VERSION 5.7 ;
  NOWIREEXTENSIONATPIN ON ;
  DIVIDERCHAR "/" ;
  BUSBITCHARS "[]" ;
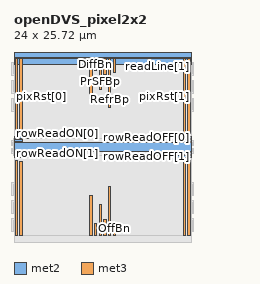
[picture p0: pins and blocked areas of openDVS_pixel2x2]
MACRO openDVS_pixel2x2
  CLASS BLOCK ;
  FOREIGN openDVS_pixel2x2 ;
  ORIGIN 17.915 13.040 ;
  SIZE 24.000 BY 25.720 ;
  PIN rowReadOFF[0]
    ANTENNAGATEAREA 0.420000 ;
    PORT
      LAYER met2 ;
        RECT -17.915 0.930 -15.840 1.190 ;
    END
    PORT
      LAYER met2 ;
        RECT 4.010 0.930 6.085 1.190 ;
    END
  END rowReadOFF[0]
  PIN rowReadON[0]
    ANTENNAGATEAREA 0.420000 ;
    PORT
      LAYER met2 ;
        RECT -17.915 0.530 -16.740 0.790 ;
    END
    PORT
      LAYER met2 ;
        RECT 4.910 0.530 6.085 0.790 ;
    END
  END rowReadON[0]
  PIN GndD
    PORT
      LAYER met2 ;
        RECT -17.915 -0.755 6.085 0.395 ;
    END
  END GndD
  PIN rowReadON[1]
    ANTENNAGATEAREA 0.420000 ;
    PORT
      LAYER met2 ;
        RECT -17.915 -1.150 -16.740 -0.890 ;
    END
    PORT
      LAYER met2 ;
        RECT 4.910 -1.150 6.085 -0.890 ;
    END
  END rowReadON[1]
  PIN rowReadOFF[1]
    ANTENNAGATEAREA 0.420000 ;
    PORT
      LAYER met2 ;
        RECT -17.915 -1.550 -15.840 -1.290 ;
    END
    PORT
      LAYER met2 ;
        RECT 4.010 -1.550 6.085 -1.290 ;
    END
  END rowReadOFF[1]
  PIN GndA
    PORT
      LAYER met2 ;
        RECT -17.915 10.960 6.085 11.750 ;
    END
  END GndA
  PIN VddA18
    PORT
      LAYER met2 ;
        RECT -17.915 11.890 6.085 12.680 ;
    END
  END VddA18
  PIN OffBn
    ANTENNAGATEAREA 9.000000 ;
    PORT
      LAYER met3 ;
        RECT -4.505 -12.180 -4.175 -10.205 ;
    END
    PORT
      LAYER met3 ;
        RECT -4.505 9.845 -4.175 11.820 ;
    END
  END OffBn
  PIN readLine[0]
    ANTENNAGATEAREA 0.126000 ;
    PORT
      LAYER met3 ;
        RECT -17.135 1.735 -16.805 11.820 ;
    END
    PORT
      LAYER met3 ;
        RECT -17.135 -12.180 -16.805 -2.095 ;
    END
  END readLine[0]
  PIN pixRst[1]
    ANTENNADIFFAREA 0.252000 ;
    PORT
      LAYER met3 ;
        RECT 5.605 1.610 5.935 11.820 ;
    END
    PORT
      LAYER met3 ;
        RECT 5.605 -12.180 5.935 -1.970 ;
    END
  END pixRst[1]
  PIN readLine[1]
    ANTENNAGATEAREA 0.126000 ;
    PORT
      LAYER met3 ;
        RECT 4.975 1.735 5.305 11.820 ;
    END
    PORT
      LAYER met3 ;
        RECT 4.975 -12.180 5.305 -2.095 ;
    END
  END readLine[1]
  PIN pixRst[0]
    ANTENNADIFFAREA 0.252000 ;
    PORT
      LAYER met3 ;
        RECT -17.765 1.610 -17.435 11.820 ;
    END
    PORT
      LAYER met3 ;
        RECT -17.765 -12.180 -17.435 -1.970 ;
    END
  END pixRst[0]
  PIN OnBn
    ANTENNAGATEAREA 9.000000 ;
    PORT
      LAYER met3 ;
        RECT -7.655 6.370 -7.325 11.820 ;
    END
    PORT
      LAYER met3 ;
        RECT -7.655 -12.180 -7.325 -6.730 ;
    END
  END OnBn
  PIN DiffBn
    ANTENNAGATEAREA 9.000000 ;
    PORT
      LAYER met3 ;
        RECT -7.025 10.120 -6.695 11.820 ;
    END
    PORT
      LAYER met3 ;
        RECT -7.025 -12.180 -6.695 -10.480 ;
    END
  END DiffBn
  PIN PrSFBp
    ANTENNAGATEAREA 2.520000 ;
    PORT
      LAYER met3 ;
        RECT -6.395 7.565 -6.065 11.820 ;
    END
    PORT
      LAYER met3 ;
        RECT -6.395 -12.180 -6.065 -7.925 ;
    END
  END PrSFBp
  PIN PrBp
    ANTENNAGATEAREA 0.300000 ;
    ANTENNADIFFAREA 1.404000 ;
    PORT
      LAYER met3 ;
        RECT -5.765 9.580 -5.435 11.820 ;
    END
    PORT
      LAYER met3 ;
        RECT -5.765 -12.180 -5.435 -9.940 ;
    END
  END PrBp
  PIN RefrBp
    ANTENNAGATEAREA 2.520000 ;
    PORT
      LAYER met3 ;
        RECT -5.135 5.230 -4.805 11.820 ;
    END
    PORT
      LAYER met3 ;
        RECT -5.135 -12.180 -4.805 -5.590 ;
    END
  END RefrBp
  OBS
      LAYER nwell ;
        RECT -17.915 11.315 6.085 11.895 ;
      LAYER pwell ;
        RECT -18.195 9.555 -15.835 11.315 ;
      LAYER nwell ;
        RECT -15.835 9.555 4.005 11.315 ;
      LAYER pwell ;
        RECT 4.005 9.555 6.365 11.315 ;
      LAYER nwell ;
        RECT -17.915 8.875 6.085 9.555 ;
      LAYER pwell ;
        RECT -18.195 7.115 -15.835 8.875 ;
      LAYER nwell ;
        RECT -15.835 7.115 4.005 8.875 ;
      LAYER pwell ;
        RECT 4.005 7.115 6.365 8.875 ;
      LAYER nwell ;
        RECT -17.915 6.435 6.085 7.115 ;
      LAYER pwell ;
        RECT -18.195 4.675 -15.835 6.435 ;
      LAYER nwell ;
        RECT -15.835 4.675 4.005 6.435 ;
      LAYER pwell ;
        RECT 4.005 4.675 6.365 6.435 ;
      LAYER nwell ;
        RECT -17.915 0.675 6.085 4.675 ;
      LAYER pwell ;
        RECT -18.195 -0.005 -14.035 0.675 ;
      LAYER nwell ;
        RECT -14.035 -0.005 2.205 0.675 ;
      LAYER pwell ;
        RECT 2.205 -0.005 6.365 0.675 ;
      LAYER nwell ;
        RECT -17.915 -0.355 6.085 -0.005 ;
      LAYER pwell ;
        RECT -18.195 -1.035 -14.035 -0.355 ;
      LAYER nwell ;
        RECT -14.035 -1.035 2.205 -0.355 ;
      LAYER pwell ;
        RECT 2.205 -1.035 6.365 -0.355 ;
      LAYER nwell ;
        RECT -17.915 -5.035 6.085 -1.035 ;
      LAYER pwell ;
        RECT -18.195 -6.795 -15.835 -5.035 ;
      LAYER nwell ;
        RECT -15.835 -6.795 4.005 -5.035 ;
      LAYER pwell ;
        RECT 4.005 -6.795 6.365 -5.035 ;
      LAYER nwell ;
        RECT -17.915 -7.475 6.085 -6.795 ;
      LAYER pwell ;
        RECT -18.195 -9.235 -15.835 -7.475 ;
      LAYER nwell ;
        RECT -15.835 -9.235 4.005 -7.475 ;
      LAYER pwell ;
        RECT 4.005 -9.235 6.365 -7.475 ;
      LAYER nwell ;
        RECT -17.915 -9.915 6.085 -9.235 ;
      LAYER pwell ;
        RECT -18.195 -11.675 -15.835 -9.915 ;
      LAYER nwell ;
        RECT -15.835 -11.675 4.005 -9.915 ;
      LAYER pwell ;
        RECT 4.005 -11.675 6.365 -9.915 ;
      LAYER nwell ;
        RECT -17.915 -12.255 6.085 -11.675 ;
      LAYER li1 ;
        RECT -17.915 11.140 6.085 11.635 ;
        RECT -18.000 9.730 6.170 11.140 ;
        RECT -17.915 8.700 6.085 9.730 ;
        RECT -18.000 7.290 6.170 8.700 ;
        RECT -17.915 6.260 6.085 7.290 ;
        RECT -18.000 4.850 6.170 6.260 ;
        RECT -17.915 0.500 6.085 4.850 ;
        RECT -18.000 0.170 6.170 0.500 ;
        RECT -17.915 -0.530 6.085 0.170 ;
        RECT -18.000 -0.860 6.170 -0.530 ;
        RECT -17.915 -5.210 6.085 -0.860 ;
        RECT -18.000 -6.620 6.170 -5.210 ;
        RECT -17.915 -7.650 6.085 -6.620 ;
        RECT -18.000 -9.060 6.170 -7.650 ;
        RECT -17.915 -10.090 6.085 -9.060 ;
        RECT -18.000 -11.500 6.170 -10.090 ;
        RECT -17.915 -11.995 6.085 -11.500 ;
      LAYER met1 ;
        RECT -17.915 11.120 6.085 11.665 ;
        RECT -18.030 9.750 6.200 11.120 ;
        RECT -17.915 8.680 6.085 9.750 ;
        RECT -18.030 7.310 6.200 8.680 ;
        RECT -17.915 6.240 6.085 7.310 ;
        RECT -18.030 4.870 6.200 6.240 ;
        RECT -17.915 0.480 6.085 4.870 ;
        RECT -18.060 0.190 6.230 0.480 ;
        RECT -17.915 -0.550 6.085 0.190 ;
        RECT -18.060 -0.840 6.230 -0.550 ;
        RECT -17.915 -5.230 6.085 -0.840 ;
        RECT -18.030 -6.600 6.200 -5.230 ;
        RECT -17.915 -7.670 6.085 -6.600 ;
        RECT -18.030 -9.040 6.200 -7.670 ;
        RECT -17.915 -10.110 6.085 -9.040 ;
        RECT -18.030 -11.480 6.200 -10.110 ;
        RECT -17.915 -12.025 6.085 -11.480 ;
      LAYER met2 ;
        RECT -17.915 1.470 6.085 10.680 ;
        RECT -15.560 0.675 3.730 1.470 ;
        RECT -15.560 -1.830 3.730 -1.035 ;
        RECT -17.915 -13.040 6.085 -1.830 ;
      LAYER met3 ;
        RECT -16.405 5.970 -8.055 11.565 ;
        RECT -6.925 7.165 -6.795 9.720 ;
        RECT -3.775 9.445 4.575 11.565 ;
        RECT -5.665 7.165 -5.535 9.180 ;
        RECT -6.925 5.970 -5.535 7.165 ;
        RECT -16.405 4.830 -5.535 5.970 ;
        RECT -4.405 4.830 4.575 9.445 ;
        RECT -16.405 1.335 4.575 4.830 ;
        RECT -17.035 1.210 5.205 1.335 ;
        RECT -17.765 -1.570 5.935 1.210 ;
        RECT -17.035 -1.695 5.205 -1.570 ;
        RECT -16.405 -5.190 4.575 -1.695 ;
        RECT -16.405 -6.330 -5.535 -5.190 ;
        RECT -16.405 -11.925 -8.055 -6.330 ;
        RECT -6.925 -7.525 -5.535 -6.330 ;
        RECT -6.925 -10.080 -6.795 -7.525 ;
        RECT -5.665 -9.540 -5.535 -7.525 ;
        RECT -4.405 -9.805 4.575 -5.190 ;
        RECT -3.775 -11.925 4.575 -9.805 ;
      LAYER met4 ;
        RECT -17.915 0.905 6.085 11.820 ;
        RECT -17.920 -1.265 6.090 0.905 ;
        RECT -17.915 -12.180 6.085 -1.265 ;
  END
END openDVS_pixel2x2
END LIBRARY

